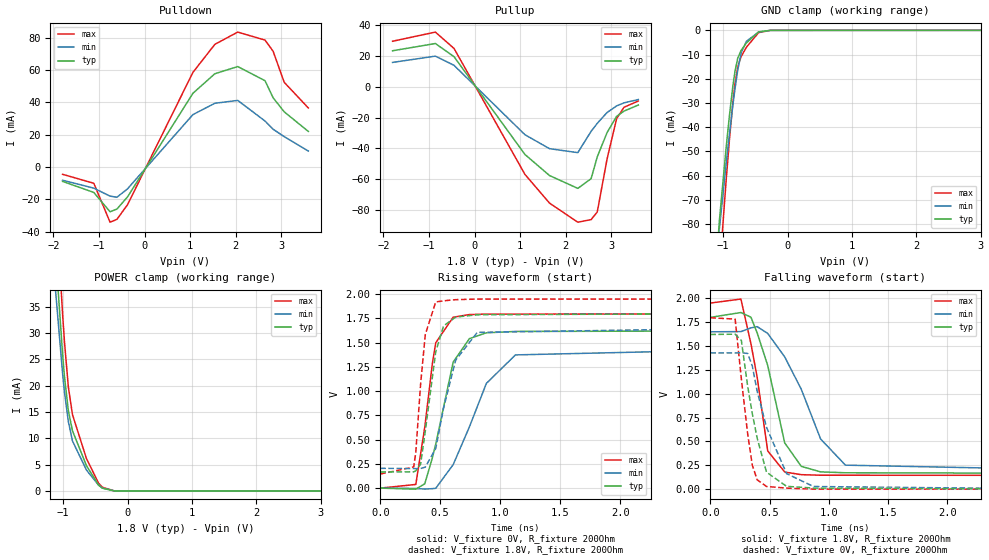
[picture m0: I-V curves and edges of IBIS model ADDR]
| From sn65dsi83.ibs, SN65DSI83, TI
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|   Model
[Model]   ADDR
Model_type   I/O
Polarity   Non-Inverting
Enable   Active-Low
Vinl = 0.54
Vinh = 1.26
Vmeas = 0.9
Vref = 0
Cref = 1pF
Rref = 10000
|   typ   min   max
C_comp   0.4630pF   0.3789pF   0.6229pF
[Voltage Range]   1.8   1.65   1.95
[Temperature Range]   27   125   -40
[Pullup Reference]   1.8   1.65   1.95
[Pulldown Reference]   -0   -0   -0
[Power Clamp Reference]   1.8   1.65   1.95
[GND Clamp Reference]   -0   -0   -0
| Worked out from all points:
|   slope of the pulldown table from 0 to 0.27 V, typ, clamps not added: 20.6 ohm
|   slope of the pullup table from 0 to 0.27 V, typ, clamps not added: 22.3 ohm
|   GND clamp passes 1 mA (typ) near -0.46 V on its own axis
|   POWER clamp passes 1 mA (typ) near -0.44 V on its own axis
|   falling waveform, V_fixture 1.8V, R_fixture 200Ohm: 20-80 % time 186ps typ, 306ps min, 135ps max; typ from 1.8 V to 0.167 V
|   rising waveform, V_fixture 0V, R_fixture 200Ohm: 20-80 % time 170ps typ, 292ps min, 112ps max; typ from 0 V to 1.62 V
|   rising waveform, V_fixture 1.8V, R_fixture 200Ohm: 20-80 % time 107ps typ, 165ps min, 71.5ps max; typ from 0.167 V to 1.8 V
|   falling waveform, V_fixture 0V, R_fixture 200Ohm: 20-80 % time 145ps typ, 208ps min, 99.7ps max; typ from 1.62 V to 0 V
[Pulldown]
|   Voltage   I(typ)   I(min)   I(max)
-1.8V     -8.944mA   -8.235mA   -4.562mA
-1.114V   -15.8mA    -13.15mA   -10.13mA
-757.8mV  -27.74mA   -18.05mA   -34.18mA
-606.6mV  -26.07mA   -18.76mA   -32.41mA
-374.4mV  -18.55mA   -13.55mA   -23.38mA
1.062V    45.55mA    32.36mA    58.49mA
1.543V    57.62mA    39.35mA    75.79mA
2.045V    62.06mA    41.12mA    83.37mA
2.644V    53.32mA    28.38mA    78.42mA
2.822V    42.75mA    23.29mA    71.52mA
3.065V    34.07mA    18.73mA    52.33mA
3.595V    21.94mA    9.811mA    36.44mA
[GND Clamp]
|   Voltage   I(typ)   I(min)   I(max)
-1.8V     -365.9mA   -331.5mA   -431.2mA
-1.06V    -78.98mA   -82.24mA   -100.4mA
-952.2mV  -48.1mA    -54.78mA   -61.49mA
-903.6mV  -35.48mA   -43.14mA   -45.61mA
-849.6mV  -23.12mA   -31.03mA   -29.92mA
-817.2mV  -17.09mA   -24.36mA   -22.2mA
-774mV    -11.57mA   -16.51mA   -15.13mA
-720mV    -8.222mA   -9.272mA   -10.82mA
-639mV    -5.235mA   -4.533mA   -6.997mA
-450mV    -639.8uA   -729.1uA   -952.1uA
-266.4mV  -7.244uA   -17.61uA   -9.882uA
3.595V    0A         0A         0A
[Pullup]
|   Voltage   I(typ)   I(min)   I(max)
-1.8V     23.39mA    15.83mA    29.57mA
-860.4mV  28.1mA     19.91mA    35.51mA
-450mV    19.54mA    13.93mA    24.86mA
1.105V    -43.86mA   -31.05mA   -56.77mA
1.645V    -57.54mA   -40.13mA   -75.43mA
2.266V    -65.88mA   -42.69mA   -87.82mA
2.558V    -59.6mA    -28.9mA    -86.14mA
2.693V    -45.47mA   -23.7mA    -81.24mA
2.909V    -29.66mA   -16.65mA   -46.78mA
3.119V    -19.11mA   -12.37mA   -20.55mA
3.281V    -15.75mA   -10.4mA    -13.25mA
3.595V    -11.8mA    -8.235mA   -9.174mA
[POWER Clamp]
|   Voltage   I(typ)   I(min)   I(max)
-1.8V     199mA      166.7mA    232.1mA
-1.136V   48.46mA    40.77mA    60.31mA
-1.125V   46.37mA    39.03mA    57.88mA
-1.006V   25.5mA     21.9mA     33.07mA
-979.2mV  21.68mA    18.73mA    28.27mA
-919.8mV  15.28mA    13.2mA     19.79mA
-855mV    11.4mA     9.486mA    14.47mA
-639mV    4.811mA    3.978mA    6.176mA
-450mV    1.136mA    1.099mA    1.482mA
-390.6mV  522.3uA    551.4uA    697.5uA
-207mV    5.854uA    12.5uA     9.961uA
3.595V    0A         0A         0A
[Ramp]
R_load = 200
|   typ   min   max
dV/dt_r   0.972411/1.69676e-10   0.855528/2.91185e-10   1.07754/1.1156e-10
dV/dt_f   0.979876/1.85387e-10   0.866595/3.0597e-10   1.08306/1.34833e-10
[Falling Waveform]
V_fixture = 1.8V
V_fixture_min = 1.65V
V_fixture_max = 1.95V
R_fixture = 200Ohm
C_fixture = 0F
|   Time   V(typ)   V(min)   V(max)
0s        1.8V       1.649V     1.95V
258.4ps   1.851V     1.651V     1.992V
343.1ps   1.802V     1.69V      1.523V
395.3ps   1.638V     1.703V     1.174V
484.3ps   1.297V     1.632V     400.6mV
627.8ps   484.9mV    1.386V     179.8mV
767.4ps   239.1mV    1.047V     151.8mV
930.4ps   181.3mV    525.8mV    146.1mV
1.14ns    171.8mV    251.6mV    146mV
3ns       166.9mV    204.9mV    144.9mV
[Rising Waveform]
V_fixture = 0V
V_fixture_min = 0V
V_fixture_max = 0V
R_fixture = 200Ohm
C_fixture = 0F
|   Time   V(typ)   V(min)   V(max)
0s        21.86uV    715.5uV    748.1nV
296.3ps   -10.95mV   -3.704mV   37.73mV
371.1ps   44.67mV    -9.622mV   629.5mV
435.1ps   316.1mV    -5.576mV   1.293V
462.3ps   453.3mV    -2.002mV   1.499V
607.8ps   1.3V       242mV      1.763V
743.4ps   1.542V     632.4mV    1.79V
884.5ps   1.602V     1.08V      1.795V
1.127ns   1.616V     1.374V     1.795V
3ns       1.621V     1.427V     1.796V
[Rising Waveform]
V_fixture = 1.8V
V_fixture_min = 1.65V
V_fixture_max = 1.95V
R_fixture = 200Ohm
C_fixture = 0F
|   Time   V(typ)   V(min)   V(max)
0s        166.6mV    204.1mV    144.9mV
279ps     168mV      201.4mV    218.4mV
296.3ps   178.7mV    201.3mV    372.1mV
336.1ps   247.1mV    202.1mV    1.071V
375.4ps   588.6mV    216.9mV    1.585V
462.3ps   1.406V     408.5mV    1.92V
527.6ps   1.673V     825.8mV    1.932V
628.9ps   1.764V     1.321V     1.944V
808.6ps   1.788V     1.606V     1.95V
3ns       1.8V       1.648V     1.95V
[Falling Waveform]
|Gnd
V_fixture = 0V
V_fixture_min = 0V
V_fixture_max = 0V
R_fixture = 200Ohm
C_fixture = 0F
|   Time   V(typ)   V(min)   V(max)
0s        1.621V     1.428V     1.796V
209.8ps   1.624V     1.427V     1.782V
262.3ps   1.557V     1.43V      1.152V
315.3ps   1.079V     1.422V     580.1mV
354.1ps   794.2mV    1.293V     252.3mV
395.3ps   535mV      1.028V     98.12mV
474.3ps   178.2mV    647.9mV    28.27mV
643.5ps   29.61mV    163mV      11mV
870ps     11.51mV    27.93mV    1.006mV
3ns       234.7uV    1.411mV    1.146uV
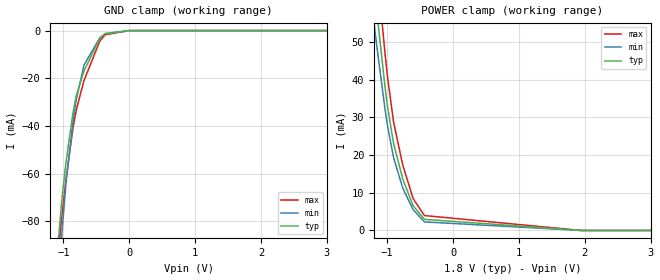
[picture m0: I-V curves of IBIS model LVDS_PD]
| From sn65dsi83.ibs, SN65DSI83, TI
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|   Model
[Model]   LVDS_PD
Model_type   Terminator
|   typ   min   max
C_comp   0.2021pF   0.1391pF   0.2894pF
[Voltage Range]   1.8   1.65   1.95
[Temperature Range]   27   125   -40
[Power Clamp Reference]   1.8   1.65   1.95
[GND Clamp Reference]   -0   -0   -0
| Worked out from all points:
|   GND clamp passes 1 mA (typ) near -0.35 V on its own axis
[GND Clamp]
|   Voltage   I(typ)   I(min)   I(max)
-1.8V     -663.1mA   -698.6mA   -653.5mA
-1.076V   -87.76mA   -108.9mA   -93.13mA
-1.033V   -73.68mA   -89.29mA   -80.32mA
-1.017V   -69.09mA   -82.84mA   -75.97mA
-963mV    -55.63mA   -64.52mA   -62.74mA
-855mV    -34.47mA   -38.19mA   -40.93mA
-806.4mV  -27.5mA    -29.09mA   -33.43mA
-687.6mV  -16.89mA   -14.43mA   -20.91mA
-450mV    -3.382mA   -3.11mA    -4.536mA
-369mV    -1.298mA   -1.317mA   -1.755mA
-1.8mV    -2.71uA    -2.3uA     -3.365uA
3.595V    0A         0A         0A
[POWER Clamp]
|   Voltage   I(typ)   I(min)   I(max)
-1.8V     191.4mA    166mA      218mA
-1.217V   68.57mA    57.69mA    81.85mA
-1.179V   61.78mA    52mA       74.18mA
-1.163V   58.94mA    49.62mA    70.95mA
-1.033V   38.05mA    32.17mA    46.94mA
-995.4mV  32.89mA    27.82mA    40.81mA
-903.6mV  23.13mA    19.32mA    28.84mA
-763.2mV  13.65mA    11.23mA    17.32mA
-606.6mV  6.528mA    5.497mA    8.485mA
-433.8mV  2.955mA    2.273mA    3.958mA
1.948V    0A         0A         4.321uA
3.595V    0A         0A         0A
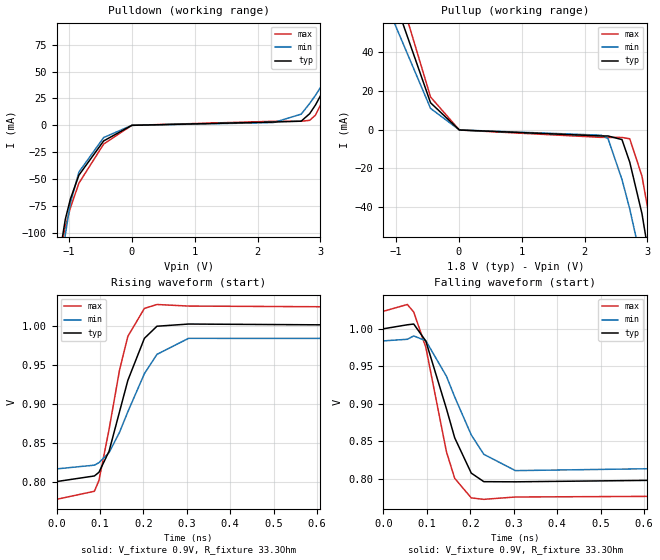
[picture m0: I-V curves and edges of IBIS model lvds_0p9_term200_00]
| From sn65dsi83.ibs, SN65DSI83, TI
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|   Model
[Model]   lvds_0p9_term200_00
Model_type   Output
Polarity   Non-Inverting
Vmeas = 0.9
Vref = 0.9
Cref = 1pF
Rref = 50
|   typ   min   max
C_comp   0.4797pF   0.3035pF   0.7186pF
[Voltage Range]   1.8   1.65   1.95
[Temperature Range]   27   125   -40
[Pullup Reference]   1.8   1.65   1.95
[Pulldown Reference]   -0   -0   -0
[Power Clamp Reference]   1.8   1.65   1.95
[GND Clamp Reference]   -0   -0   -0
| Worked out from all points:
|   slope of the pulldown table from 0 to 0.27 V, typ, clamps not added: 103 ohm
|   slope of the pullup table from 0 to 0.27 V, typ, clamps not added: 125 ohm
|   falling waveform, V_fixture 0.9V, R_fixture 33.3Ohm: 20-80 % time 59.6ps typ, 76.8ps min, 52.1ps max; typ from 1 V to 0.801 V
|   rising waveform, V_fixture 0.9V, R_fixture 33.3Ohm: 20-80 % time 59.8ps typ, 82ps min, 50.9ps max; typ from 0.801 V to 1 V
[Pulldown]
|   Voltage   I(typ)   I(min)   I(max)
-1.8V     -662.7mA   -697.8mA   -653.1mA
-1.13V    -112.7mA   -137.9mA   -115.4mA
-1.06V    -87.36mA   -101.6mA   -94.27mA
-979.2mV  -68.51mA   -72.26mA   -76.75mA
-844.2mV  -46.38mA   -43.5mA    -53.83mA
-450mV    -14.52mA   -11.38mA   -17.44mA
-1.8mV    -33.53uA   -25.47uA   -40.8uA
2.255V    3.033mA    2.558mA    3.733mA
2.693V    3.827mA    10.38mA    3.765mA
2.828V    10.8mA     20.31mA    4.631mA
2.92V     18.84mA    27.89mA    9.433mA
3.595V    91.51mA    89.23mA    89.04mA
[Pullup]
|   Voltage   I(typ)   I(min)   I(max)
-1.8V     228.2mA    197.4mA    256mA
-1.384V   134.6mA    112.6mA    154.7mA
-1.022V   67mA       54.82mA    78.78mA
-450mV    13.92mA    11.02mA    16.91mA
9mV       -129.5uA   -102.2uA   -153.1uA
2.266V    -3.208mA   -2.819mA   -3.944mA
2.374V    -3.216mA   -4.563mA   -3.957mA
2.596V    -5.081mA   -25.67mA   -3.984mA
2.72V     -16.75mA   -40.9mA    -4.667mA
2.914V    -43.26mA   -69.24mA   -23.89mA
3.152V    -90.02mA   -115.2mA   -67.23mA
3.595V    -189.8mA   -211.9mA   -167.2mA
[Ramp]
R_load = 33.3
|   typ   min   max
dV/dt_r   0.119509/5.98005e-11   0.100089/8.19725e-11   0.147074/5.08557e-11
dV/dt_f   0.119479/5.95675e-11   0.100107/7.67934e-11   0.147074/5.20593e-11
[Falling Waveform]
V_fixture = 0.9V
V_fixture_min = 0.9V
V_fixture_max = 0.9V
R_fixture = 33.3Ohm
C_fixture = 0F
|   Time   V(typ)   V(min)   V(max)
0s        999.7mV    983.6mV    1.023V
55.03ps   1.005V     985.7mV    1.032V
69.85ps   1.006V     990.2mV    1.022V
97.66ps   983.4mV    983.8mV    975mV
145.2ps   893.2mV    936.5mV    835.9mV
164.2ps   854.6mV    909mV      800.7mV
202.3ps   807.7mV    858.5mV    774.7mV
231.2ps   796.3mV    832.7mV    772.8mV
303.9ps   796.1mV    811mV      775.9mV
1ns       800.5mV    816.7mV    777.8mV
[Rising Waveform]
V_fixture = 0.9V
V_fixture_min = 0.9V
V_fixture_max = 0.9V
R_fixture = 33.3Ohm
C_fixture = 0F
|   Time   V(typ)   V(min)   V(max)
0s        800.5mV    816.7mV    777.8mV
87.21ps   807.7mV    821.5mV    788.1mV
97.66ps   812.4mV    824.7mV    801.9mV
120.9ps   839.2mV    837.5mV    867mV
145.2ps   890.1mV    863.7mV    943.5mV
164.2ps   929.9mV    889.8mV    986.2mV
202.3ps   983.7mV    938.5mV    1.022V
231.2ps   999.2mV    963.2mV    1.027V
303.9ps   1.002V     983.7mV    1.025V
1ns       999.7mV    983.6mV    1.023V
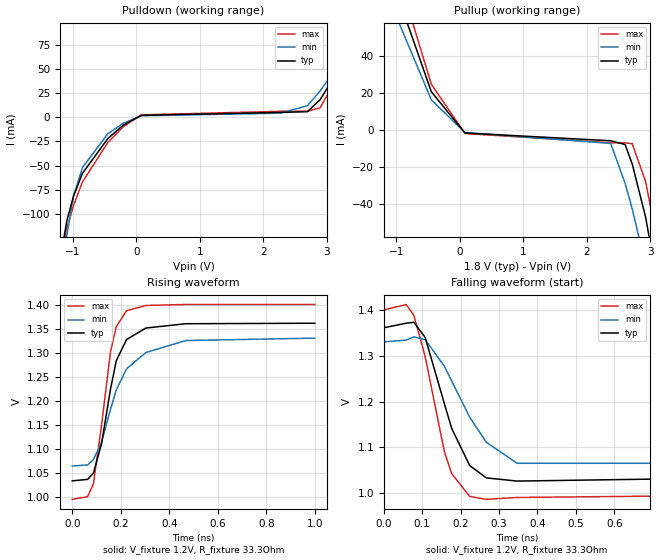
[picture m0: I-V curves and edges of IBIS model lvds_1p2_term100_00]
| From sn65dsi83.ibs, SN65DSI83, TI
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|   Model
[Model]   lvds_1p2_term100_00
Model_type   Output
Polarity   Non-Inverting
Vmeas = 1.2
Vref = 1.2
Cref = 1pF
Rref = 50
|   typ   min   max
C_comp   0.4797pF   0.3035pF   0.7186pF
[Voltage Range]   1.8   1.65   1.95
[Temperature Range]   27   125   -40
[Pullup Reference]   1.8   1.65   1.95
[Pulldown Reference]   -0   -0   -0
[Power Clamp Reference]   1.8   1.65   1.95
[GND Clamp Reference]   -0   -0   -0
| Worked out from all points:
|   slope of the pulldown table from 0 to 0.27 V, typ, clamps not added: 62.1 ohm
|   slope of the pullup table from 0 to 0.27 V, typ, clamps not added: 67.8 ohm
|   falling waveform, V_fixture 1.2V, R_fixture 33.3Ohm: 20-80 % time 70.3ps typ, 104ps min, 60.9ps max; typ from 1.36 V to 1.03 V
|   rising waveform, V_fixture 1.2V, R_fixture 33.3Ohm: 20-80 % time 75.1ps typ, 118ps min, 61ps max; typ from 1.03 V to 1.36 V
[Pulldown]
|   Voltage   I(typ)   I(min)   I(max)
-1.8V     -663.2mA   -698.2mA   -653.8mA
-1.147V   -127.1mA   -150.5mA   -131.3mA
-1.093V   -106.7mA   -121.2mA   -114.7mA
-990mV    -81.79mA   -82mA      -91.67mA
-849.6mV  -58.11mA   -52.24mA   -67.04mA
-450mV    -22.08mA   -17.1mA    -26.18mA
-201.6mV  -7.914mA   -6.018mA   -9.482mA
79.2mV    2.068mA    1.601mA    2.51mA
2.261V    5.051mA    4.257mA    6.217mA
2.693V    5.821mA    11.99mA    6.262mA
2.893V    18.2mA     27.2mA     9.841mA
3.595V    93.4mA     90.87mA    91.3mA
[Pullup]
|   Voltage   I(typ)   I(min)   I(max)
-1.8V     238.8mA    205.6mA    267.6mA
-1.4V     147.2mA    123.5mA    168.2mA
-1.039V   78.2mA     64.2mA     91.1mA
-450mV    20.51mA    16.16mA    24.56mA
79.2mV    -1.75mA    -1.499mA   -2.024mA
2.374V    -5.956mA   -7.394mA   -7.04mA
2.601V    -7.985mA   -28.93mA   -7.089mA
2.714V    -18.57mA   -42.82mA   -7.57mA
2.925V    -47.37mA   -73.58mA   -28.09mA
3.103V    -81.86mA   -107.6mA   -59.6mA
3.168V    -95.7mA    -121mA     -73.16mA
3.595V    -192mA     -214.2mA   -169.6mA
[Ramp]
R_load = 33.3
|   typ   min   max
dV/dt_r   0.196784/7.51233e-11   0.159121/1.18038e-10   0.243174/6.10476e-11
dV/dt_f   0.196865/7.03221e-11   0.159623/1.03508e-10   0.243162/6.08797e-11
[Falling Waveform]
V_fixture = 1.2V
V_fixture_min = 1.2V
V_fixture_max = 1.2V
R_fixture = 33.3Ohm
C_fixture = 0F
|   Time   V(typ)   V(min)   V(max)
0s        1.362V     1.331V     1.401V
58.42ps   1.372V     1.335V     1.413V
78.54ps   1.374V     1.342V     1.389V
107.8ps   1.341V     1.336V     1.299V
157.7ps   1.196V     1.278V     1.091V
177.1ps   1.141V     1.245V     1.042V
223.7ps   1.06V      1.166V     992.4mV
267ps     1.033V     1.111V     986mV
347ps     1.026V     1.065V     990.1mV
1ns       1.034V     1.065V     995.4mV
[Rising Waveform]
V_fixture = 1.2V
V_fixture_min = 1.2V
V_fixture_max = 1.2V
R_fixture = 33.3Ohm
C_fixture = 0F
|   Time   V(typ)   V(min)   V(max)
0s        1.034V     1.065V     995.5mV
63.2ps    1.037V     1.067V     1.001V
87.22ps   1.05V      1.078V     1.028V
121ps     1.112V     1.115V     1.151V
157.7ps   1.225V     1.183V     1.303V
181.5ps   1.284V     1.223V     1.355V
223.7ps   1.328V     1.267V     1.388V
303.4ps   1.352V     1.301V     1.399V
467.9ps   1.361V     1.326V     1.401V
1ns       1.362V     1.331V     1.401V
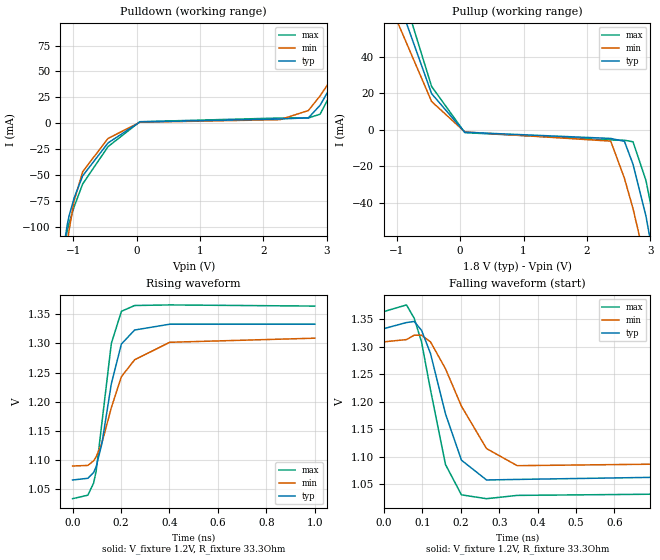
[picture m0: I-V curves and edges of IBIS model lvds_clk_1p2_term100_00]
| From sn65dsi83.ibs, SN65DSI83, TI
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|   Model
[Model]   lvds_clk_1p2_term100_00
Model_type   Output
Polarity   Non-Inverting
Vmeas = 1.2
Vref = 1.2
Cref = 1pF
Rref = 50
|   typ   min   max
C_comp   0.4797pF   0.3035pF   0.7186pF
[Voltage Range]   1.8   1.65   1.95
[Temperature Range]   27   125   -40
[Pullup Reference]   1.8   1.65   1.95
[Pulldown Reference]   -0   -0   -0
[Power Clamp Reference]   1.8   1.65   1.95
[GND Clamp Reference]   -0   -0   -0
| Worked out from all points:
|   slope of the pulldown table from 0 to 0.27 V, typ, clamps not added: 76.4 ohm
|   slope of the pullup table from 0 to 0.27 V, typ, clamps not added: 83.9 ohm
|   falling waveform, V_fixture 1.2V, R_fixture 33.3Ohm: 20-80 % time 62.1ps typ, 91.7ps min, 54.6ps max; typ from 1.33 V to 1.07 V
|   rising waveform, V_fixture 1.2V, R_fixture 33.3Ohm: 20-80 % time 68.9ps typ, 114ps min, 55.8ps max; typ from 1.07 V to 1.33 V
[Pulldown]
|   Voltage   I(typ)   I(min)   I(max)
-1.8V     -662.6mA   -697.8mA   -653.1mA
-1.13V    -112.8mA   -137.8mA   -115.6mA
-1.093V   -98.16mA   -117.2mA   -103.8mA
-1.066V   -89.99mA   -104.3mA   -97.07mA
-984.6mV  -72.23mA   -75.09mA   -80.79mA
-849.6mV  -50.82mA   -46.81mA   -58.67mA
-450mV    -19.06mA   -14.72mA   -22.64mA
52.2mV    1.21mA     935.1uA    1.468mA
2.261V    4.08mA     3.434mA    5.039mA
2.709V    5.23mA     12.28mA    5.086mA
2.893V    17.3mA     26.43mA    8.725mA
3.595V    92.49mA    90.07mA    90.23mA
[Pullup]
|   Voltage   I(typ)   I(min)   I(max)
-1.8V     237.9mA    204.6mA    266.6mA
-1.406V   147.3mA    123.3mA    168.4mA
-1.039V   77.29mA    63.22mA    90.14mA
-450mV    19.8mA     15.49mA    23.75mA
73.8mV    -1.404mA   -1.207mA   -1.609mA
2.374V    -4.792mA   -6.26mA    -5.65mA
2.59V     -6.389mA   -26.67mA   -5.765mA
2.725V    -18.91mA   -43.25mA   -6.633mA
2.93V     -47.49mA   -73.69mA   -27.87mA
3.098V    -80.01mA   -105.8mA   -57.61mA
3.168V    -95.02mA   -120.3mA   -72.31mA
3.595V    -191.5mA   -213.7mA   -169mA
[Ramp]
R_load = 33.3
|   typ   min   max
dV/dt_r   0.160522/6.89014e-11   0.131395/1.13784e-10   0.198107/5.57863e-11
dV/dt_f   0.16051/6.20507e-11   0.131681/9.16778e-11   0.19809/5.46308e-11
[Falling Waveform]
V_fixture = 1.2V
V_fixture_min = 1.2V
V_fixture_max = 1.2V
R_fixture = 33.3Ohm
C_fixture = 0F
|   Time   V(typ)   V(min)   V(max)
0s        1.333V     1.309V     1.364V
58.42ps   1.344V     1.313V     1.376V
78.52ps   1.346V     1.321V     1.352V
97.63ps   1.33V      1.321V     1.309V
120.9ps   1.288V     1.309V     1.222V
160.1ps   1.178V     1.26V      1.086V
201.6ps   1.094V     1.192V     1.031V
266.9ps   1.058V     1.115V     1.024V
346.8ps   1.059V     1.084V     1.03V
1ns       1.066V     1.089V     1.034V
[Rising Waveform]
V_fixture = 1.2V
V_fixture_min = 1.2V
V_fixture_max = 1.2V
R_fixture = 33.3Ohm
C_fixture = 0F
|   Time   V(typ)   V(min)   V(max)
0s        1.066V     1.09V      1.034V
63.2ps    1.069V     1.091V     1.04V
87.18ps   1.079V     1.099V     1.061V
97.63ps   1.089V     1.106V     1.082V
120.9ps   1.128V     1.129V     1.163V
160.1ps   1.231V     1.19V      1.3V
201.6ps   1.299V     1.243V     1.355V
256.2ps   1.323V     1.272V     1.365V
401.2ps   1.333V     1.302V     1.366V
1ns       1.333V     1.309V     1.364V
